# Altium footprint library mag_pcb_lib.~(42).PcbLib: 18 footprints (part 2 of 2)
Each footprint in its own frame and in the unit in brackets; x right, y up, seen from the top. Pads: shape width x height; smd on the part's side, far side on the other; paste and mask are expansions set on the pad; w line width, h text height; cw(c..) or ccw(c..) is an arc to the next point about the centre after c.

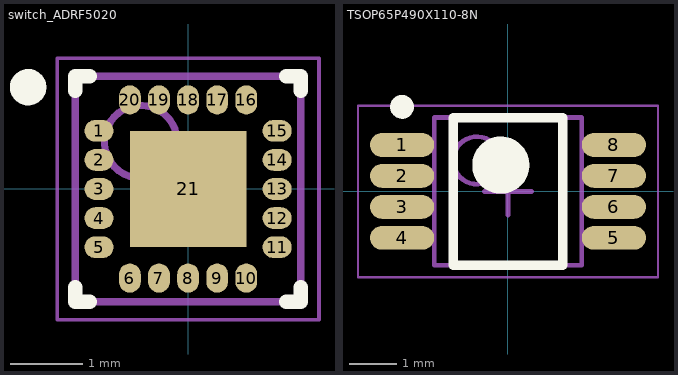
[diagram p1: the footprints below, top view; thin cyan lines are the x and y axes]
## switch_ADRF5020 [mm] "PQFN, 20-Leads, Body 3.00x3.00mm, Pitch 0.40mm, Thermal Pad 1.60x1.60mm, IPC Medium Density"
height 0.78
pads (21):
  oval 0.4x0.3 smd: 1(-1.225,0.8) 2(-1.225,0.4) 3(-1.225,0) 4(-1.225,-0.4) 5(-1.225,-0.8) 11(1.225,-0.8) 12(1.225,-0.4) 13(1.225,0) 14(1.225,0.4) 15(1.225,0.8)
  oval 0.3x0.4 smd: 6(-0.8,-1.225) 7(-0.4,-1.225) 8(0,-1.225) 9(0.4,-1.225) 10(0.8,-1.225) 16(0.8,1.225) 17(0.4,1.225) 18(0,1.225) 19(-0.4,1.225) 20(-0.8,1.225)
  rect 1.6x1.6 smd: 21(0,0)
Top Overlay:
  circle w0.25: c-2.2,1.4 r0.125
  lines w0.2: -1.55,-1.35 -1.55,-1.55 -1.35,-1.55 ; -1.55,1.35 -1.55,1.55 -1.35,1.55 ; 1.35,-1.55 1.55,-1.55 1.55,-1.35 ; 1.35,1.55 1.55,1.55 1.55,1.35
Mechanical 13:
  circle w0.1: c-0.65,0.65 r0.5
  lines w0.1: -1.55,-1.55 -1.55,1.55 1.55,1.55 1.55,-1.55 -1.55,-1.55
Mechanical 15:
  lines w0.05: -1.8,-1.8 -1.8,1.8 1.8,1.8 1.8,-1.8 -1.8,-1.8
  lines w0.1: -0.5,0 0.5,0 ; 0,-0.5 0,0.5
3D body: height 0.78, standoff 0.16, extent -1.55,-1.55 1.55,1.55

## TSOP65P490X110-8N [mm] "TSOP, 8-Leads, Body 3.00x3.00mm, Pitch 0.65mm, IPC Medium Density"
height 1.1
pads (8):
  oval 1.35x0.5 smd: 1(-2.225,0.975) 2(-2.225,0.325) 3(-2.225,-0.325) 4(-2.225,-0.975) 5(2.225,-0.975) 6(2.225,-0.325) 7(2.225,0.325) 8(2.225,0.975)
Top Overlay:
  circle w0.25: c-2.225,1.775 r0.125
  circle w0.6: c-0.15,0.55 r0.3
  lines w0.2: -1.15,-1.55 -1.15,1.55 1.15,1.55 1.15,-1.55 -1.15,-1.55
Mechanical 13:
  circle w0.1: c-0.65,0.65 r0.5
  lines w0.1: -1.55,-1.55 -1.55,1.55 1.55,1.55 1.55,-1.55 -1.55,-1.55
Mechanical 15:
  lines w0.05: -3.15,-1.8 -3.15,1.8 3.15,1.8 3.15,-1.8 -3.15,-1.8
  lines w0.1: -0.5,0 0.5,0 ; 0,-0.5 0,0.5
3D body: height 1.1, standoff 0.25, extent -1.55,-1.55 1.55,1.55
